VERSION 5.7 ;
BUSBITCHARS "[]" ;
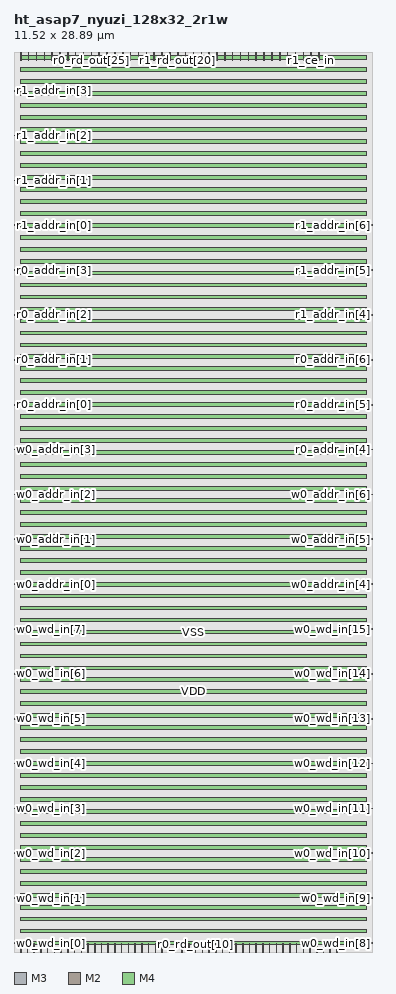
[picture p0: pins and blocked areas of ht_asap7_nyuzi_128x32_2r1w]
MACRO ht_asap7_nyuzi_128x32_2r1w
  FOREIGN ht_asap7_nyuzi_128x32_2r1w 0 0 ;
  SYMMETRY X Y R90 ;
  SIZE 11.520 BY 28.890 ;
  CLASS BLOCK ;
  PIN w0_wd_in[0]
    DIRECTION INPUT ;
    USE SIGNAL ;
    SHAPE ABUTMENT ;
    PORT
      LAYER M3 ;
      RECT 0.000 0.276 0.072 0.300 ;
    END
  END w0_wd_in[0]
  PIN w0_wd_in[1]
    DIRECTION INPUT ;
    USE SIGNAL ;
    SHAPE ABUTMENT ;
    PORT
      LAYER M3 ;
      RECT 0.000 1.716 0.072 1.740 ;
    END
  END w0_wd_in[1]
  PIN w0_wd_in[2]
    DIRECTION INPUT ;
    USE SIGNAL ;
    SHAPE ABUTMENT ;
    PORT
      LAYER M3 ;
      RECT 0.000 3.156 0.072 3.180 ;
    END
  END w0_wd_in[2]
  PIN w0_wd_in[3]
    DIRECTION INPUT ;
    USE SIGNAL ;
    SHAPE ABUTMENT ;
    PORT
      LAYER M3 ;
      RECT 0.000 4.596 0.072 4.620 ;
    END
  END w0_wd_in[3]
  PIN w0_wd_in[4]
    DIRECTION INPUT ;
    USE SIGNAL ;
    SHAPE ABUTMENT ;
    PORT
      LAYER M3 ;
      RECT 0.000 6.036 0.072 6.060 ;
    END
  END w0_wd_in[4]
  PIN w0_wd_in[5]
    DIRECTION INPUT ;
    USE SIGNAL ;
    SHAPE ABUTMENT ;
    PORT
      LAYER M3 ;
      RECT 0.000 7.476 0.072 7.500 ;
    END
  END w0_wd_in[5]
  PIN w0_wd_in[6]
    DIRECTION INPUT ;
    USE SIGNAL ;
    SHAPE ABUTMENT ;
    PORT
      LAYER M3 ;
      RECT 0.000 8.916 0.072 8.940 ;
    END
  END w0_wd_in[6]
  PIN w0_wd_in[7]
    DIRECTION INPUT ;
    USE SIGNAL ;
    SHAPE ABUTMENT ;
    PORT
      LAYER M3 ;
      RECT 0.000 10.356 0.072 10.380 ;
    END
  END w0_wd_in[7]
  PIN w0_wd_in[8]
    DIRECTION INPUT ;
    USE SIGNAL ;
    SHAPE ABUTMENT ;
    PORT
      LAYER M3 ;
      RECT 11.448 0.276 11.520 0.300 ;
    END
  END w0_wd_in[8]
  PIN w0_wd_in[9]
    DIRECTION INPUT ;
    USE SIGNAL ;
    SHAPE ABUTMENT ;
    PORT
      LAYER M3 ;
      RECT 11.448 1.716 11.520 1.740 ;
    END
  END w0_wd_in[9]
  PIN w0_wd_in[10]
    DIRECTION INPUT ;
    USE SIGNAL ;
    SHAPE ABUTMENT ;
    PORT
      LAYER M3 ;
      RECT 11.448 3.156 11.520 3.180 ;
    END
  END w0_wd_in[10]
  PIN w0_wd_in[11]
    DIRECTION INPUT ;
    USE SIGNAL ;
    SHAPE ABUTMENT ;
    PORT
      LAYER M3 ;
      RECT 11.448 4.596 11.520 4.620 ;
    END
  END w0_wd_in[11]
  PIN w0_wd_in[12]
    DIRECTION INPUT ;
    USE SIGNAL ;
    SHAPE ABUTMENT ;
    PORT
      LAYER M3 ;
      RECT 11.448 6.036 11.520 6.060 ;
    END
  END w0_wd_in[12]
  PIN w0_wd_in[13]
    DIRECTION INPUT ;
    USE SIGNAL ;
    SHAPE ABUTMENT ;
    PORT
      LAYER M3 ;
      RECT 11.448 7.476 11.520 7.500 ;
    END
  END w0_wd_in[13]
  PIN w0_wd_in[14]
    DIRECTION INPUT ;
    USE SIGNAL ;
    SHAPE ABUTMENT ;
    PORT
      LAYER M3 ;
      RECT 11.448 8.916 11.520 8.940 ;
    END
  END w0_wd_in[14]
  PIN w0_wd_in[15]
    DIRECTION INPUT ;
    USE SIGNAL ;
    SHAPE ABUTMENT ;
    PORT
      LAYER M3 ;
      RECT 11.448 10.356 11.520 10.380 ;
    END
  END w0_wd_in[15]
  PIN w0_wd_in[16]
    DIRECTION INPUT ;
    USE SIGNAL ;
    SHAPE ABUTMENT ;
    PORT
      LAYER M2 ;
      RECT 0.207 0.000 0.225 0.270 ;
    END
  END w0_wd_in[16]
  PIN w0_wd_in[17]
    DIRECTION INPUT ;
    USE SIGNAL ;
    SHAPE ABUTMENT ;
    PORT
      LAYER M2 ;
      RECT 0.423 0.000 0.441 0.270 ;
    END
  END w0_wd_in[17]
  PIN w0_wd_in[18]
    DIRECTION INPUT ;
    USE SIGNAL ;
    SHAPE ABUTMENT ;
    PORT
      LAYER M2 ;
      RECT 0.639 0.000 0.657 0.270 ;
    END
  END w0_wd_in[18]
  PIN w0_wd_in[19]
    DIRECTION INPUT ;
    USE SIGNAL ;
    SHAPE ABUTMENT ;
    PORT
      LAYER M2 ;
      RECT 0.855 0.000 0.873 0.270 ;
    END
  END w0_wd_in[19]
  PIN w0_wd_in[20]
    DIRECTION INPUT ;
    USE SIGNAL ;
    SHAPE ABUTMENT ;
    PORT
      LAYER M2 ;
      RECT 1.071 0.000 1.089 0.270 ;
    END
  END w0_wd_in[20]
  PIN w0_wd_in[21]
    DIRECTION INPUT ;
    USE SIGNAL ;
    SHAPE ABUTMENT ;
    PORT
      LAYER M2 ;
      RECT 1.287 0.000 1.305 0.270 ;
    END
  END w0_wd_in[21]
  PIN w0_wd_in[22]
    DIRECTION INPUT ;
    USE SIGNAL ;
    SHAPE ABUTMENT ;
    PORT
      LAYER M2 ;
      RECT 1.503 0.000 1.521 0.270 ;
    END
  END w0_wd_in[22]
  PIN w0_wd_in[23]
    DIRECTION INPUT ;
    USE SIGNAL ;
    SHAPE ABUTMENT ;
    PORT
      LAYER M2 ;
      RECT 1.719 0.000 1.737 0.270 ;
    END
  END w0_wd_in[23]
  PIN w0_wd_in[24]
    DIRECTION INPUT ;
    USE SIGNAL ;
    SHAPE ABUTMENT ;
    PORT
      LAYER M2 ;
      RECT 1.935 0.000 1.953 0.270 ;
    END
  END w0_wd_in[24]
  PIN w0_wd_in[25]
    DIRECTION INPUT ;
    USE SIGNAL ;
    SHAPE ABUTMENT ;
    PORT
      LAYER M2 ;
      RECT 2.151 0.000 2.169 0.270 ;
    END
  END w0_wd_in[25]
  PIN w0_wd_in[26]
    DIRECTION INPUT ;
    USE SIGNAL ;
    SHAPE ABUTMENT ;
    PORT
      LAYER M2 ;
      RECT 2.367 0.000 2.385 0.270 ;
    END
  END w0_wd_in[26]
  PIN w0_wd_in[27]
    DIRECTION INPUT ;
    USE SIGNAL ;
    SHAPE ABUTMENT ;
    PORT
      LAYER M2 ;
      RECT 2.583 0.000 2.601 0.270 ;
    END
  END w0_wd_in[27]
  PIN w0_wd_in[28]
    DIRECTION INPUT ;
    USE SIGNAL ;
    SHAPE ABUTMENT ;
    PORT
      LAYER M2 ;
      RECT 2.799 0.000 2.817 0.270 ;
    END
  END w0_wd_in[28]
  PIN w0_wd_in[29]
    DIRECTION INPUT ;
    USE SIGNAL ;
    SHAPE ABUTMENT ;
    PORT
      LAYER M2 ;
      RECT 3.015 0.000 3.033 0.270 ;
    END
  END w0_wd_in[29]
  PIN w0_wd_in[30]
    DIRECTION INPUT ;
    USE SIGNAL ;
    SHAPE ABUTMENT ;
    PORT
      LAYER M2 ;
      RECT 3.231 0.000 3.249 0.270 ;
    END
  END w0_wd_in[30]
  PIN w0_wd_in[31]
    DIRECTION INPUT ;
    USE SIGNAL ;
    SHAPE ABUTMENT ;
    PORT
      LAYER M2 ;
      RECT 3.447 0.000 3.465 0.270 ;
    END
  END w0_wd_in[31]
  PIN r0_rd_out[0]
    DIRECTION OUTPUT ;
    USE SIGNAL ;
    SHAPE ABUTMENT ;
    PORT
      LAYER M2 ;
      RECT 3.663 0.000 3.681 0.270 ;
    END
  END r0_rd_out[0]
  PIN r0_rd_out[1]
    DIRECTION OUTPUT ;
    USE SIGNAL ;
    SHAPE ABUTMENT ;
    PORT
      LAYER M2 ;
      RECT 3.879 0.000 3.897 0.270 ;
    END
  END r0_rd_out[1]
  PIN r0_rd_out[2]
    DIRECTION OUTPUT ;
    USE SIGNAL ;
    SHAPE ABUTMENT ;
    PORT
      LAYER M2 ;
      RECT 4.095 0.000 4.113 0.270 ;
    END
  END r0_rd_out[2]
  PIN r0_rd_out[3]
    DIRECTION OUTPUT ;
    USE SIGNAL ;
    SHAPE ABUTMENT ;
    PORT
      LAYER M2 ;
      RECT 4.311 0.000 4.329 0.270 ;
    END
  END r0_rd_out[3]
  PIN r0_rd_out[4]
    DIRECTION OUTPUT ;
    USE SIGNAL ;
    SHAPE ABUTMENT ;
    PORT
      LAYER M2 ;
      RECT 4.527 0.000 4.545 0.270 ;
    END
  END r0_rd_out[4]
  PIN r0_rd_out[5]
    DIRECTION OUTPUT ;
    USE SIGNAL ;
    SHAPE ABUTMENT ;
    PORT
      LAYER M2 ;
      RECT 4.743 0.000 4.761 0.270 ;
    END
  END r0_rd_out[5]
  PIN r0_rd_out[6]
    DIRECTION OUTPUT ;
    USE SIGNAL ;
    SHAPE ABUTMENT ;
    PORT
      LAYER M2 ;
      RECT 4.959 0.000 4.977 0.270 ;
    END
  END r0_rd_out[6]
  PIN r0_rd_out[7]
    DIRECTION OUTPUT ;
    USE SIGNAL ;
    SHAPE ABUTMENT ;
    PORT
      LAYER M2 ;
      RECT 5.175 0.000 5.193 0.270 ;
    END
  END r0_rd_out[7]
  PIN r0_rd_out[8]
    DIRECTION OUTPUT ;
    USE SIGNAL ;
    SHAPE ABUTMENT ;
    PORT
      LAYER M2 ;
      RECT 5.391 0.000 5.409 0.270 ;
    END
  END r0_rd_out[8]
  PIN r0_rd_out[9]
    DIRECTION OUTPUT ;
    USE SIGNAL ;
    SHAPE ABUTMENT ;
    PORT
      LAYER M2 ;
      RECT 5.607 0.000 5.625 0.270 ;
    END
  END r0_rd_out[9]
  PIN r0_rd_out[10]
    DIRECTION OUTPUT ;
    USE SIGNAL ;
    SHAPE ABUTMENT ;
    PORT
      LAYER M2 ;
      RECT 5.823 0.000 5.841 0.270 ;
    END
  END r0_rd_out[10]
  PIN r0_rd_out[11]
    DIRECTION OUTPUT ;
    USE SIGNAL ;
    SHAPE ABUTMENT ;
    PORT
      LAYER M2 ;
      RECT 6.039 0.000 6.057 0.270 ;
    END
  END r0_rd_out[11]
  PIN r0_rd_out[12]
    DIRECTION OUTPUT ;
    USE SIGNAL ;
    SHAPE ABUTMENT ;
    PORT
      LAYER M2 ;
      RECT 6.255 0.000 6.273 0.270 ;
    END
  END r0_rd_out[12]
  PIN r0_rd_out[13]
    DIRECTION OUTPUT ;
    USE SIGNAL ;
    SHAPE ABUTMENT ;
    PORT
      LAYER M2 ;
      RECT 6.471 0.000 6.489 0.270 ;
    END
  END r0_rd_out[13]
  PIN r0_rd_out[14]
    DIRECTION OUTPUT ;
    USE SIGNAL ;
    SHAPE ABUTMENT ;
    PORT
      LAYER M2 ;
      RECT 6.687 0.000 6.705 0.270 ;
    END
  END r0_rd_out[14]
  PIN r0_rd_out[15]
    DIRECTION OUTPUT ;
    USE SIGNAL ;
    SHAPE ABUTMENT ;
    PORT
      LAYER M2 ;
      RECT 6.903 0.000 6.921 0.270 ;
    END
  END r0_rd_out[15]
  PIN r0_rd_out[16]
    DIRECTION OUTPUT ;
    USE SIGNAL ;
    SHAPE ABUTMENT ;
    PORT
      LAYER M2 ;
      RECT 0.207 28.620 0.225 28.890 ;
    END
  END r0_rd_out[16]
  PIN r0_rd_out[17]
    DIRECTION OUTPUT ;
    USE SIGNAL ;
    SHAPE ABUTMENT ;
    PORT
      LAYER M2 ;
      RECT 0.459 28.620 0.477 28.890 ;
    END
  END r0_rd_out[17]
  PIN r0_rd_out[18]
    DIRECTION OUTPUT ;
    USE SIGNAL ;
    SHAPE ABUTMENT ;
    PORT
      LAYER M2 ;
      RECT 0.711 28.620 0.729 28.890 ;
    END
  END r0_rd_out[18]
  PIN r0_rd_out[19]
    DIRECTION OUTPUT ;
    USE SIGNAL ;
    SHAPE ABUTMENT ;
    PORT
      LAYER M2 ;
      RECT 0.963 28.620 0.981 28.890 ;
    END
  END r0_rd_out[19]
  PIN r0_rd_out[20]
    DIRECTION OUTPUT ;
    USE SIGNAL ;
    SHAPE ABUTMENT ;
    PORT
      LAYER M2 ;
      RECT 1.215 28.620 1.233 28.890 ;
    END
  END r0_rd_out[20]
  PIN r0_rd_out[21]
    DIRECTION OUTPUT ;
    USE SIGNAL ;
    SHAPE ABUTMENT ;
    PORT
      LAYER M2 ;
      RECT 1.467 28.620 1.485 28.890 ;
    END
  END r0_rd_out[21]
  PIN r0_rd_out[22]
    DIRECTION OUTPUT ;
    USE SIGNAL ;
    SHAPE ABUTMENT ;
    PORT
      LAYER M2 ;
      RECT 1.719 28.620 1.737 28.890 ;
    END
  END r0_rd_out[22]
  PIN r0_rd_out[23]
    DIRECTION OUTPUT ;
    USE SIGNAL ;
    SHAPE ABUTMENT ;
    PORT
      LAYER M2 ;
      RECT 1.971 28.620 1.989 28.890 ;
    END
  END r0_rd_out[23]
  PIN r0_rd_out[24]
    DIRECTION OUTPUT ;
    USE SIGNAL ;
    SHAPE ABUTMENT ;
    PORT
      LAYER M2 ;
      RECT 2.223 28.620 2.241 28.890 ;
    END
  END r0_rd_out[24]
  PIN r0_rd_out[25]
    DIRECTION OUTPUT ;
    USE SIGNAL ;
    SHAPE ABUTMENT ;
    PORT
      LAYER M2 ;
      RECT 2.475 28.620 2.493 28.890 ;
    END
  END r0_rd_out[25]
  PIN r0_rd_out[26]
    DIRECTION OUTPUT ;
    USE SIGNAL ;
    SHAPE ABUTMENT ;
    PORT
      LAYER M2 ;
      RECT 2.727 28.620 2.745 28.890 ;
    END
  END r0_rd_out[26]
  PIN r0_rd_out[27]
    DIRECTION OUTPUT ;
    USE SIGNAL ;
    SHAPE ABUTMENT ;
    PORT
      LAYER M2 ;
      RECT 2.979 28.620 2.997 28.890 ;
    END
  END r0_rd_out[27]
  PIN r0_rd_out[28]
    DIRECTION OUTPUT ;
    USE SIGNAL ;
    SHAPE ABUTMENT ;
    PORT
      LAYER M2 ;
      RECT 3.231 28.620 3.249 28.890 ;
    END
  END r0_rd_out[28]
  PIN r0_rd_out[29]
    DIRECTION OUTPUT ;
    USE SIGNAL ;
    SHAPE ABUTMENT ;
    PORT
      LAYER M2 ;
      RECT 3.483 28.620 3.501 28.890 ;
    END
  END r0_rd_out[29]
  PIN r0_rd_out[30]
    DIRECTION OUTPUT ;
    USE SIGNAL ;
    SHAPE ABUTMENT ;
    PORT
      LAYER M2 ;
      RECT 3.735 28.620 3.753 28.890 ;
    END
  END r0_rd_out[30]
  PIN r0_rd_out[31]
    DIRECTION OUTPUT ;
    USE SIGNAL ;
    SHAPE ABUTMENT ;
    PORT
      LAYER M2 ;
      RECT 3.987 28.620 4.005 28.890 ;
    END
  END r0_rd_out[31]
  PIN r1_rd_out[0]
    DIRECTION OUTPUT ;
    USE SIGNAL ;
    SHAPE ABUTMENT ;
    PORT
      LAYER M2 ;
      RECT 7.119 0.000 7.137 0.270 ;
    END
  END r1_rd_out[0]
  PIN r1_rd_out[1]
    DIRECTION OUTPUT ;
    USE SIGNAL ;
    SHAPE ABUTMENT ;
    PORT
      LAYER M2 ;
      RECT 7.335 0.000 7.353 0.270 ;
    END
  END r1_rd_out[1]
  PIN r1_rd_out[2]
    DIRECTION OUTPUT ;
    USE SIGNAL ;
    SHAPE ABUTMENT ;
    PORT
      LAYER M2 ;
      RECT 7.551 0.000 7.569 0.270 ;
    END
  END r1_rd_out[2]
  PIN r1_rd_out[3]
    DIRECTION OUTPUT ;
    USE SIGNAL ;
    SHAPE ABUTMENT ;
    PORT
      LAYER M2 ;
      RECT 7.767 0.000 7.785 0.270 ;
    END
  END r1_rd_out[3]
  PIN r1_rd_out[4]
    DIRECTION OUTPUT ;
    USE SIGNAL ;
    SHAPE ABUTMENT ;
    PORT
      LAYER M2 ;
      RECT 7.983 0.000 8.001 0.270 ;
    END
  END r1_rd_out[4]
  PIN r1_rd_out[5]
    DIRECTION OUTPUT ;
    USE SIGNAL ;
    SHAPE ABUTMENT ;
    PORT
      LAYER M2 ;
      RECT 8.199 0.000 8.217 0.270 ;
    END
  END r1_rd_out[5]
  PIN r1_rd_out[6]
    DIRECTION OUTPUT ;
    USE SIGNAL ;
    SHAPE ABUTMENT ;
    PORT
      LAYER M2 ;
      RECT 8.415 0.000 8.433 0.270 ;
    END
  END r1_rd_out[6]
  PIN r1_rd_out[7]
    DIRECTION OUTPUT ;
    USE SIGNAL ;
    SHAPE ABUTMENT ;
    PORT
      LAYER M2 ;
      RECT 8.631 0.000 8.649 0.270 ;
    END
  END r1_rd_out[7]
  PIN r1_rd_out[8]
    DIRECTION OUTPUT ;
    USE SIGNAL ;
    SHAPE ABUTMENT ;
    PORT
      LAYER M2 ;
      RECT 8.847 0.000 8.865 0.270 ;
    END
  END r1_rd_out[8]
  PIN r1_rd_out[9]
    DIRECTION OUTPUT ;
    USE SIGNAL ;
    SHAPE ABUTMENT ;
    PORT
      LAYER M2 ;
      RECT 9.063 0.000 9.081 0.270 ;
    END
  END r1_rd_out[9]
  PIN r1_rd_out[10]
    DIRECTION OUTPUT ;
    USE SIGNAL ;
    SHAPE ABUTMENT ;
    PORT
      LAYER M2 ;
      RECT 9.279 0.000 9.297 0.270 ;
    END
  END r1_rd_out[10]
  PIN r1_rd_out[11]
    DIRECTION OUTPUT ;
    USE SIGNAL ;
    SHAPE ABUTMENT ;
    PORT
      LAYER M2 ;
      RECT 9.495 0.000 9.513 0.270 ;
    END
  END r1_rd_out[11]
  PIN r1_rd_out[12]
    DIRECTION OUTPUT ;
    USE SIGNAL ;
    SHAPE ABUTMENT ;
    PORT
      LAYER M2 ;
      RECT 9.711 0.000 9.729 0.270 ;
    END
  END r1_rd_out[12]
  PIN r1_rd_out[13]
    DIRECTION OUTPUT ;
    USE SIGNAL ;
    SHAPE ABUTMENT ;
    PORT
      LAYER M2 ;
      RECT 9.927 0.000 9.945 0.270 ;
    END
  END r1_rd_out[13]
  PIN r1_rd_out[14]
    DIRECTION OUTPUT ;
    USE SIGNAL ;
    SHAPE ABUTMENT ;
    PORT
      LAYER M2 ;
      RECT 10.143 0.000 10.161 0.270 ;
    END
  END r1_rd_out[14]
  PIN r1_rd_out[15]
    DIRECTION OUTPUT ;
    USE SIGNAL ;
    SHAPE ABUTMENT ;
    PORT
      LAYER M2 ;
      RECT 10.359 0.000 10.377 0.270 ;
    END
  END r1_rd_out[15]
  PIN r1_rd_out[16]
    DIRECTION OUTPUT ;
    USE SIGNAL ;
    SHAPE ABUTMENT ;
    PORT
      LAYER M2 ;
      RECT 4.239 28.620 4.257 28.890 ;
    END
  END r1_rd_out[16]
  PIN r1_rd_out[17]
    DIRECTION OUTPUT ;
    USE SIGNAL ;
    SHAPE ABUTMENT ;
    PORT
      LAYER M2 ;
      RECT 4.491 28.620 4.509 28.890 ;
    END
  END r1_rd_out[17]
  PIN r1_rd_out[18]
    DIRECTION OUTPUT ;
    USE SIGNAL ;
    SHAPE ABUTMENT ;
    PORT
      LAYER M2 ;
      RECT 4.743 28.620 4.761 28.890 ;
    END
  END r1_rd_out[18]
  PIN r1_rd_out[19]
    DIRECTION OUTPUT ;
    USE SIGNAL ;
    SHAPE ABUTMENT ;
    PORT
      LAYER M2 ;
      RECT 4.995 28.620 5.013 28.890 ;
    END
  END r1_rd_out[19]
  PIN r1_rd_out[20]
    DIRECTION OUTPUT ;
    USE SIGNAL ;
    SHAPE ABUTMENT ;
    PORT
      LAYER M2 ;
      RECT 5.247 28.620 5.265 28.890 ;
    END
  END r1_rd_out[20]
  PIN r1_rd_out[21]
    DIRECTION OUTPUT ;
    USE SIGNAL ;
    SHAPE ABUTMENT ;
    PORT
      LAYER M2 ;
      RECT 5.499 28.620 5.517 28.890 ;
    END
  END r1_rd_out[21]
  PIN r1_rd_out[22]
    DIRECTION OUTPUT ;
    USE SIGNAL ;
    SHAPE ABUTMENT ;
    PORT
      LAYER M2 ;
      RECT 5.751 28.620 5.769 28.890 ;
    END
  END r1_rd_out[22]
  PIN r1_rd_out[23]
    DIRECTION OUTPUT ;
    USE SIGNAL ;
    SHAPE ABUTMENT ;
    PORT
      LAYER M2 ;
      RECT 6.003 28.620 6.021 28.890 ;
    END
  END r1_rd_out[23]
  PIN r1_rd_out[24]
    DIRECTION OUTPUT ;
    USE SIGNAL ;
    SHAPE ABUTMENT ;
    PORT
      LAYER M2 ;
      RECT 6.255 28.620 6.273 28.890 ;
    END
  END r1_rd_out[24]
  PIN r1_rd_out[25]
    DIRECTION OUTPUT ;
    USE SIGNAL ;
    SHAPE ABUTMENT ;
    PORT
      LAYER M2 ;
      RECT 6.507 28.620 6.525 28.890 ;
    END
  END r1_rd_out[25]
  PIN r1_rd_out[26]
    DIRECTION OUTPUT ;
    USE SIGNAL ;
    SHAPE ABUTMENT ;
    PORT
      LAYER M2 ;
      RECT 6.759 28.620 6.777 28.890 ;
    END
  END r1_rd_out[26]
  PIN r1_rd_out[27]
    DIRECTION OUTPUT ;
    USE SIGNAL ;
    SHAPE ABUTMENT ;
    PORT
      LAYER M2 ;
      RECT 7.011 28.620 7.029 28.890 ;
    END
  END r1_rd_out[27]
  PIN r1_rd_out[28]
    DIRECTION OUTPUT ;
    USE SIGNAL ;
    SHAPE ABUTMENT ;
    PORT
      LAYER M2 ;
      RECT 7.263 28.620 7.281 28.890 ;
    END
  END r1_rd_out[28]
  PIN r1_rd_out[29]
    DIRECTION OUTPUT ;
    USE SIGNAL ;
    SHAPE ABUTMENT ;
    PORT
      LAYER M2 ;
      RECT 7.515 28.620 7.533 28.890 ;
    END
  END r1_rd_out[29]
  PIN r1_rd_out[30]
    DIRECTION OUTPUT ;
    USE SIGNAL ;
    SHAPE ABUTMENT ;
    PORT
      LAYER M2 ;
      RECT 7.767 28.620 7.785 28.890 ;
    END
  END r1_rd_out[30]
  PIN r1_rd_out[31]
    DIRECTION OUTPUT ;
    USE SIGNAL ;
    SHAPE ABUTMENT ;
    PORT
      LAYER M2 ;
      RECT 8.019 28.620 8.037 28.890 ;
    END
  END r1_rd_out[31]
  PIN w0_addr_in[0]
    DIRECTION INPUT ;
    USE SIGNAL ;
    SHAPE ABUTMENT ;
    PORT
      LAYER M3 ;
      RECT 0.000 11.796 0.072 11.820 ;
    END
  END w0_addr_in[0]
  PIN w0_addr_in[1]
    DIRECTION INPUT ;
    USE SIGNAL ;
    SHAPE ABUTMENT ;
    PORT
      LAYER M3 ;
      RECT 0.000 13.236 0.072 13.260 ;
    END
  END w0_addr_in[1]
  PIN w0_addr_in[2]
    DIRECTION INPUT ;
    USE SIGNAL ;
    SHAPE ABUTMENT ;
    PORT
      LAYER M3 ;
      RECT 0.000 14.676 0.072 14.700 ;
    END
  END w0_addr_in[2]
  PIN w0_addr_in[3]
    DIRECTION INPUT ;
    USE SIGNAL ;
    SHAPE ABUTMENT ;
    PORT
      LAYER M3 ;
      RECT 0.000 16.116 0.072 16.140 ;
    END
  END w0_addr_in[3]
  PIN w0_addr_in[4]
    DIRECTION INPUT ;
    USE SIGNAL ;
    SHAPE ABUTMENT ;
    PORT
      LAYER M3 ;
      RECT 11.448 11.796 11.520 11.820 ;
    END
  END w0_addr_in[4]
  PIN w0_addr_in[5]
    DIRECTION INPUT ;
    USE SIGNAL ;
    SHAPE ABUTMENT ;
    PORT
      LAYER M3 ;
      RECT 11.448 13.236 11.520 13.260 ;
    END
  END w0_addr_in[5]
  PIN w0_addr_in[6]
    DIRECTION INPUT ;
    USE SIGNAL ;
    SHAPE ABUTMENT ;
    PORT
      LAYER M3 ;
      RECT 11.448 14.676 11.520 14.700 ;
    END
  END w0_addr_in[6]
  PIN r0_addr_in[0]
    DIRECTION INPUT ;
    USE SIGNAL ;
    SHAPE ABUTMENT ;
    PORT
      LAYER M3 ;
      RECT 0.000 17.556 0.072 17.580 ;
    END
  END r0_addr_in[0]
  PIN r0_addr_in[1]
    DIRECTION INPUT ;
    USE SIGNAL ;
    SHAPE ABUTMENT ;
    PORT
      LAYER M3 ;
      RECT 0.000 18.996 0.072 19.020 ;
    END
  END r0_addr_in[1]
  PIN r0_addr_in[2]
    DIRECTION INPUT ;
    USE SIGNAL ;
    SHAPE ABUTMENT ;
    PORT
      LAYER M3 ;
      RECT 0.000 20.436 0.072 20.460 ;
    END
  END r0_addr_in[2]
  PIN r0_addr_in[3]
    DIRECTION INPUT ;
    USE SIGNAL ;
    SHAPE ABUTMENT ;
    PORT
      LAYER M3 ;
      RECT 0.000 21.876 0.072 21.900 ;
    END
  END r0_addr_in[3]
  PIN r0_addr_in[4]
    DIRECTION INPUT ;
    USE SIGNAL ;
    SHAPE ABUTMENT ;
    PORT
      LAYER M3 ;
      RECT 11.448 16.116 11.520 16.140 ;
    END
  END r0_addr_in[4]
  PIN r0_addr_in[5]
    DIRECTION INPUT ;
    USE SIGNAL ;
    SHAPE ABUTMENT ;
    PORT
      LAYER M3 ;
      RECT 11.448 17.556 11.520 17.580 ;
    END
  END r0_addr_in[5]
  PIN r0_addr_in[6]
    DIRECTION INPUT ;
    USE SIGNAL ;
    SHAPE ABUTMENT ;
    PORT
      LAYER M3 ;
      RECT 11.448 18.996 11.520 19.020 ;
    END
  END r0_addr_in[6]
  PIN r1_addr_in[0]
    DIRECTION INPUT ;
    USE SIGNAL ;
    SHAPE ABUTMENT ;
    PORT
      LAYER M3 ;
      RECT 0.000 23.316 0.072 23.340 ;
    END
  END r1_addr_in[0]
  PIN r1_addr_in[1]
    DIRECTION INPUT ;
    USE SIGNAL ;
    SHAPE ABUTMENT ;
    PORT
      LAYER M3 ;
      RECT 0.000 24.756 0.072 24.780 ;
    END
  END r1_addr_in[1]
  PIN r1_addr_in[2]
    DIRECTION INPUT ;
    USE SIGNAL ;
    SHAPE ABUTMENT ;
    PORT
      LAYER M3 ;
      RECT 0.000 26.196 0.072 26.220 ;
    END
  END r1_addr_in[2]
  PIN r1_addr_in[3]
    DIRECTION INPUT ;
    USE SIGNAL ;
    SHAPE ABUTMENT ;
    PORT
      LAYER M3 ;
      RECT 0.000 27.636 0.072 27.660 ;
    END
  END r1_addr_in[3]
  PIN r1_addr_in[4]
    DIRECTION INPUT ;
    USE SIGNAL ;
    SHAPE ABUTMENT ;
    PORT
      LAYER M3 ;
      RECT 11.448 20.436 11.520 20.460 ;
    END
  END r1_addr_in[4]
  PIN r1_addr_in[5]
    DIRECTION INPUT ;
    USE SIGNAL ;
    SHAPE ABUTMENT ;
    PORT
      LAYER M3 ;
      RECT 11.448 21.876 11.520 21.900 ;
    END
  END r1_addr_in[5]
  PIN r1_addr_in[6]
    DIRECTION INPUT ;
    USE SIGNAL ;
    SHAPE ABUTMENT ;
    PORT
      LAYER M3 ;
      RECT 11.448 23.316 11.520 23.340 ;
    END
  END r1_addr_in[6]
  PIN w0_we_in
    DIRECTION INPUT ;
    USE SIGNAL ;
    SHAPE ABUTMENT ;
    PORT
      LAYER M2 ;
      RECT 8.271 28.620 8.289 28.890 ;
    END
  END w0_we_in
  PIN w0_ce_in
    DIRECTION INPUT ;
    USE SIGNAL ;
    SHAPE ABUTMENT ;
    PORT
      LAYER M2 ;
      RECT 8.523 28.620 8.541 28.890 ;
    END
  END w0_ce_in
  PIN w0_clk
    DIRECTION INPUT ;
    USE SIGNAL ;
    SHAPE ABUTMENT ;
    PORT
      LAYER M2 ;
      RECT 8.775 28.620 8.793 28.890 ;
    END
  END w0_clk
  PIN r0_ce_in
    DIRECTION INPUT ;
    USE SIGNAL ;
    SHAPE ABUTMENT ;
    PORT
      LAYER M2 ;
      RECT 9.027 28.620 9.045 28.890 ;
    END
  END r0_ce_in
  PIN r0_clk
    DIRECTION INPUT ;
    USE SIGNAL ;
    SHAPE ABUTMENT ;
    PORT
      LAYER M2 ;
      RECT 9.279 28.620 9.297 28.890 ;
    END
  END r0_clk
  PIN r1_ce_in
    DIRECTION INPUT ;
    USE SIGNAL ;
    SHAPE ABUTMENT ;
    PORT
      LAYER M2 ;
      RECT 9.531 28.620 9.549 28.890 ;
    END
  END r1_ce_in
  PIN r1_clk
    DIRECTION INPUT ;
    USE SIGNAL ;
    SHAPE ABUTMENT ;
    PORT
      LAYER M2 ;
      RECT 9.783 28.620 9.801 28.890 ;
    END
  END r1_clk
  PIN VSS
    DIRECTION INOUT ;
    USE GROUND ;
    PORT
      LAYER M4 ;
      RECT 0.216 0.228 11.304 0.348 ;
      RECT 0.216 0.996 11.304 1.116 ;
      RECT 0.216 1.764 11.304 1.884 ;
      RECT 0.216 2.532 11.304 2.652 ;
      RECT 0.216 3.300 11.304 3.420 ;
      RECT 0.216 4.068 11.304 4.188 ;
      RECT 0.216 4.836 11.304 4.956 ;
      RECT 0.216 5.604 11.304 5.724 ;
      RECT 0.216 6.372 11.304 6.492 ;
      RECT 0.216 7.140 11.304 7.260 ;
      RECT 0.216 7.908 11.304 8.028 ;
      RECT 0.216 8.676 11.304 8.796 ;
      RECT 0.216 9.444 11.304 9.564 ;
      RECT 0.216 10.212 11.304 10.332 ;
      RECT 0.216 10.980 11.304 11.100 ;
      RECT 0.216 11.748 11.304 11.868 ;
      RECT 0.216 12.516 11.304 12.636 ;
      RECT 0.216 13.284 11.304 13.404 ;
      RECT 0.216 14.052 11.304 14.172 ;
      RECT 0.216 14.820 11.304 14.940 ;
      RECT 0.216 15.588 11.304 15.708 ;
      RECT 0.216 16.356 11.304 16.476 ;
      RECT 0.216 17.124 11.304 17.244 ;
      RECT 0.216 17.892 11.304 18.012 ;
      RECT 0.216 18.660 11.304 18.780 ;
      RECT 0.216 19.428 11.304 19.548 ;
      RECT 0.216 20.196 11.304 20.316 ;
      RECT 0.216 20.964 11.304 21.084 ;
      RECT 0.216 21.732 11.304 21.852 ;
      RECT 0.216 22.500 11.304 22.620 ;
      RECT 0.216 23.268 11.304 23.388 ;
      RECT 0.216 24.036 11.304 24.156 ;
      RECT 0.216 24.804 11.304 24.924 ;
      RECT 0.216 25.572 11.304 25.692 ;
      RECT 0.216 26.340 11.304 26.460 ;
      RECT 0.216 27.108 11.304 27.228 ;
      RECT 0.216 27.876 11.304 27.996 ;
      RECT 0.216 28.644 11.304 28.764 ;
    END
  END VSS
  PIN VDD
    DIRECTION INOUT ;
    USE POWER ;
    PORT
      LAYER M4 ;
      RECT 0.216 0.612 11.304 0.732 ;
      RECT 0.216 1.380 11.304 1.500 ;
      RECT 0.216 2.148 11.304 2.268 ;
      RECT 0.216 2.916 11.304 3.036 ;
      RECT 0.216 3.684 11.304 3.804 ;
      RECT 0.216 4.452 11.304 4.572 ;
      RECT 0.216 5.220 11.304 5.340 ;
      RECT 0.216 5.988 11.304 6.108 ;
      RECT 0.216 6.756 11.304 6.876 ;
      RECT 0.216 7.524 11.304 7.644 ;
      RECT 0.216 8.292 11.304 8.412 ;
      RECT 0.216 9.060 11.304 9.180 ;
      RECT 0.216 9.828 11.304 9.948 ;
      RECT 0.216 10.596 11.304 10.716 ;
      RECT 0.216 11.364 11.304 11.484 ;
      RECT 0.216 12.132 11.304 12.252 ;
      RECT 0.216 12.900 11.304 13.020 ;
      RECT 0.216 13.668 11.304 13.788 ;
      RECT 0.216 14.436 11.304 14.556 ;
      RECT 0.216 15.204 11.304 15.324 ;
      RECT 0.216 15.972 11.304 16.092 ;
      RECT 0.216 16.740 11.304 16.860 ;
      RECT 0.216 17.508 11.304 17.628 ;
      RECT 0.216 18.276 11.304 18.396 ;
      RECT 0.216 19.044 11.304 19.164 ;
      RECT 0.216 19.812 11.304 19.932 ;
      RECT 0.216 20.580 11.304 20.700 ;
      RECT 0.216 21.348 11.304 21.468 ;
      RECT 0.216 22.116 11.304 22.236 ;
      RECT 0.216 22.884 11.304 23.004 ;
      RECT 0.216 23.652 11.304 23.772 ;
      RECT 0.216 24.420 11.304 24.540 ;
      RECT 0.216 25.188 11.304 25.308 ;
      RECT 0.216 25.956 11.304 26.076 ;
      RECT 0.216 26.724 11.304 26.844 ;
      RECT 0.216 27.492 11.304 27.612 ;
      RECT 0.216 28.260 11.304 28.380 ;
    END
  END VDD
  OBS
    LAYER M1 ;
    RECT 0 0 11.520 28.890 ;
    LAYER M2 ;
    RECT 0 0 11.520 28.890 ;
    LAYER M3 ;
    RECT 0 0 11.520 28.890 ;
    LAYER M4 ;
    RECT 0 0 11.520 28.890 ;
  END
END ht_asap7_nyuzi_128x32_2r1w

END LIBRARY
